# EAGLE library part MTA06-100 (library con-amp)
AMP connector

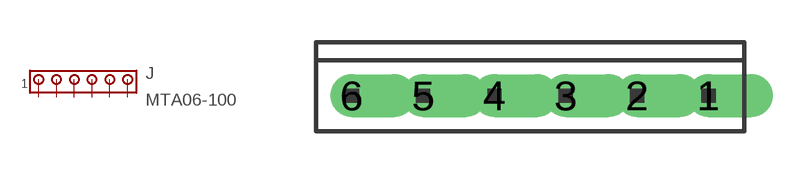
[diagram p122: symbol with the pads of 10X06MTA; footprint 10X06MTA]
Designator prefix J

## MTA06-100  [10X06MTA]
1  6  pas
2  5  pas
3  4  pas
4  3  pas
5  2  pas
6  1  pas

## Footprint 10X06MTA (pad centres in mm)
AMP MTA connector
drill 1.016 offset: 1 6.35,0; 2 3.81,0; 3 1.27,0; 4 -1.27,0; 5 -3.81,0; 6 -6.35,0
